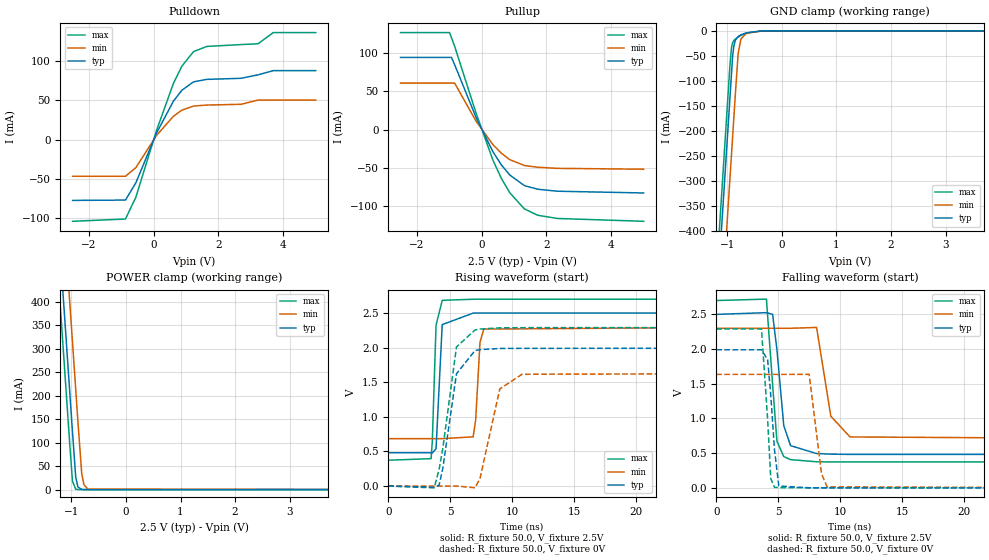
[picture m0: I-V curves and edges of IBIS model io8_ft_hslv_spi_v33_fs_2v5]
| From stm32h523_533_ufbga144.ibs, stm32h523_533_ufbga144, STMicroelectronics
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[Model]   io8_ft_hslv_spi_v33_fs_2v5
Model_type I/O
Polarity   Non-Inverting
Enable   Active-Low
| CAP_THRESHOLD on pad IOFT is "UDTCAPC" :
| Rising=20.0% of vddiom   Falling=80.0% of vddiom
| C_comp min and max val. don't necessarily correlate with the min and max pvt
| but are the smallest and greatest pad capacitance found.
| var   typ   min   max
C_comp   3.86841pF  3.83555pF  3.96274pF
|C_comp_pullup   2.45380pF  2.33565pF  2.34210pF
|C_comp_pulldown   1.41461pF  1.49990pF  1.62064pF
Vinl = 690.0mV
Vinh = 1.89V
Vmeas = 1.25V   | Reference voltage for timing measurements
Cref  = 50.0pF   | Timing specification test load capacitance value
Rref  = 100.0MOhm   | Timing specification test load resistance value
Vref  = 1.25V   | Timing specification test load voltage
[Model Spec]
| TIME_THRESHOLD on pin ZIV33M is "CMOS" :
| Rising=40.0% of vddiom   Falling=60.0% of vddiom
Vinl 978.80000mV 906.80000mV 1.05480V
Vinh 1.39920V 1.29220V 1.48720V
| variable   typ   min   max
[Temperature Range] 25.0 125.0 -40.0
| variable   typ   min   max
[Voltage Range] 2.5V 2.3V 2.7V
| variable   typ   min   max
[POWER Clamp Reference] 2.5V 2.3V 2.7V
| variable   typ   min   max
[GND Clamp Reference] 0V 0V 0V
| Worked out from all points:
|   slope of the pulldown table from 0 to 0.375 V, typ, clamps not added: 11.5 ohm
|   slope of the pullup table from 0 to 0.375 V, typ, clamps not added: 12.3 ohm
|   GND clamp passes 1 mA (typ) near -0.52 V on its own axis
|   POWER clamp passes 1 mA (typ) near -0.84 V on its own axis
|   rising waveform, R_fixture 50.0, V_fixture 2.5V: 20-80 % time 254ps typ, 282ps min, 245ps max; typ from 0.481 V to 2.5 V
|   falling waveform, R_fixture 50.0, V_fixture 2.5V: 20-80 % time 609ps typ, 780ps min, 487ps max; typ from 2.5 V to 0.481 V
|   rising waveform, R_fixture 50.0, V_fixture 0V: 20-80 % time 929ps typ, 1.15ns min, 979ps max; typ from 0 V to 1.99 V
|   falling waveform, R_fixture 50.0, V_fixture 0V: 20-80 % time 481ps typ, 588ps min, 376ps max; typ from 1.99 V to 0 V
[POWER Clamp]
-2.5V     2.708A     2.899A     2.597A
-1.23V    548.8mA    740.2mA    437.5mA
-1.16V    429.8mA    621.2mA    318.5mA
-1.12V    361.8mA    553.2mA    250.5mA
-1.03V    208.8mA    400.2mA    97.53mA
-980mV    123.8mA    315.2mA    17.95mA
-920mV    26.3mA     213.2mA    906uA
-880mV    5.543mA    145.2mA    123.7uA
-810mV    363.5uA    33.6mA     3.797uA
-770mV    76.62uA    10.47mA    518.8nA
-700mV    5.026uA    1.361mA    16.09nA
5V        0A         0A         0A
[GND Clamp]
-2.5V     -2.77A     -2.931A    -2.704A
-1.21V    -576.8mA   -738.1mA   -511.3mA
-950mV    -134.8mA   -296.1mA   -69.34mA
-920mV    -83.82mA   -245.1mA   -32.48mA
-900mV    -50.56mA   -211.1mA   -24.02mA
-880mV    -31.31mA   -177.1mA   -19.85mA
-850mV    -18.7mA    -126.1mA   -16.34mA
-800mV    -11.46mA   -46.18mA   -12.45mA
-750mV    -8.203mA   -16.63mA   -9.325mA
-650mV    -4.063mA   -4.987mA   -4.427mA
-360mV    -35.05uA   -165.1uA   -9.564uA
5V        7.96nA     1.282uA    294pA
| variable   typ   min   max
[Pullup Reference] 2.5V 2.3V 2.7V
| variable   typ   min   max
[Pulldown Reference] 0V 0V 0V
[Pullup]
-2.5V     94.45mA    60.85mA    126.9mA
-990mV    94.45mA    60.85mA    126.9mA
-930mV    94.45mA    60.85mA    120.4mA
-830mV    84.85mA    60.85mA    108.9mA
-170mV    16.04mA    11.14mA    21.66mA
350mV     -28.77mA   -19.46mA   -39.69mA
610mV     -45.89mA   -30.7mA    -63.55mA
870mV     -59.15mA   -39.06mA   -82.32mA
1.32V     -72.97mA   -46.73mA   -103.4mA
1.73V     -77.7mA    -49.01mA   -111.7mA
2.34V     -80.33mA   -50.46mA   -115.9mA
5V        -82.59mA   -51.55mA   -119.6mA
[Pulldown]
-2.5V     -77.63mA   -46.85mA   -104.3mA
-870mV    -77.24mA   -46.85mA   -101.4mA
-550mV    -55.3mA    -35.88mA   -73.72mA
90mV      8.401mA    5.299mA    11.79mA
610mV     49.03mA    29.76mA    71.69mA
870mV     62.92mA    37.48mA    93.62mA
1.23V     73.63mA    42.72mA    112.2mA
1.64V     76.78mA    44.01mA    118.8mA
2.7V      78.15mA    44.99mA    121.2mA
3.22V     82.58mA    50.35mA    122.2mA
3.69V     87.93mA    50.35mA    136.5mA
5V        87.93mA    50.35mA    136.5mA
[Ramp]
dV/dt_r 1.19372V/924.90149ps 981.18147mV/1.14692ns 1.37325V/977.3904ps
dV/dt_f 1.21165V/608.18888ps 969.26199mV/760.35677ps 1.39628V/486.33544ps
R_load = 50.0
| Removed startup time: 0s 0s 0s  .
| Removed end time: 33.75ns.
[Rising Waveform]
R_fixture   = 50.0
V_fixture   = 2.5V
V_fixture_min = 2.3V
V_fixture_max = 2.7V
0s        480.6mV    684.6mV    372.9mV
3.45ns    481mV      684.6mV    395.6mV
3.55ns    478mV      684.6mV    651.1mV
3.85ns    538.8mV    684.6mV    2.324V
4.35ns    2.332V     684.6mV    2.683V
6.85ns    2.498V     710.6mV    2.698V
7.05ns    2.499V     954.1mV    2.699V
7.4ns     2.499V     2.075V     2.699V
7.7ns     2.499V     2.267V     2.699V
33.75ns   2.5V       2.3V       2.7V
| Removed startup time: 0s 0s 0s  .
| Removed end time: 58.75ns.
[Falling Waveform]
R_fixture   = 50.0
V_fixture   = 2.5V
V_fixture_min = 2.3V
V_fixture_max = 2.7V
0s        2.5V       2.3V       2.7V
4.05ns    2.525V     2.3V       2.72V
4.55ns    2.501V     2.3V       1.486V
4.9ns     1.987V     2.3V       670.2mV
5.45ns    896.5mV    2.3V       450.3mV
6ns       608.3mV    2.3V       407mV
8.1ns     494.4mV    2.312V     375.9mV
9.25ns    485.8mV    1.033V     373.9mV
10.8ns    482.1mV    733.7mV    373.1mV
58.75ns   480.6mV    684.6mV    372.9mV
| Removed startup time: 0s 0s 0s  .
| Removed end time: 58.7ns.
[Rising Waveform]
R_fixture   = 50.0
V_fixture   = 0V
V_fixture_min = 0V
V_fixture_max = 0V
0s        184.3nV    425.6nV    144.4nV
3.7ns     -17.77mV   -118.8nV   -26.28mV
4.1ns     13.84mV    -230.2nV   241.7mV
4.4ns     259.3mV    -229.3nV   549mV
5.5ns     1.622V     -2.504uV   2.009V
7ns       1.958V     -24.91mV   2.255V
7.4ns     1.97V      110.4mV    2.268V
9ns       1.987V     1.403V     2.285V
10.8ns    1.989V     1.615V     2.288V
58.7ns    1.99V      1.635V     2.289V
| Removed startup time: 0s 0s 0s  .
| Removed end time: 33.7ns.
[Falling Waveform]
R_fixture   = 50.0
V_fixture   = 0V
V_fixture_min = 0V
V_fixture_max = 0V
0s        1.99V      1.635V     2.289V
3.65ns    1.99V      1.635V     2.291V
4.15ns    1.845V     1.635V     978.7mV
4.4ns     1.332V     1.635V     132.5mV
4.7ns     552.4mV    1.635V     7.328mV
5.05ns    26.41mV    1.635V     3.603mV
7.5ns     999.1uV    1.636V     594.7uV
8.5ns     511.2uV    202.5mV    284.8uV
8.95ns    384uV      14.72mV    207.7uV
33.7ns    197.6nV    2.782uV    38.82nV
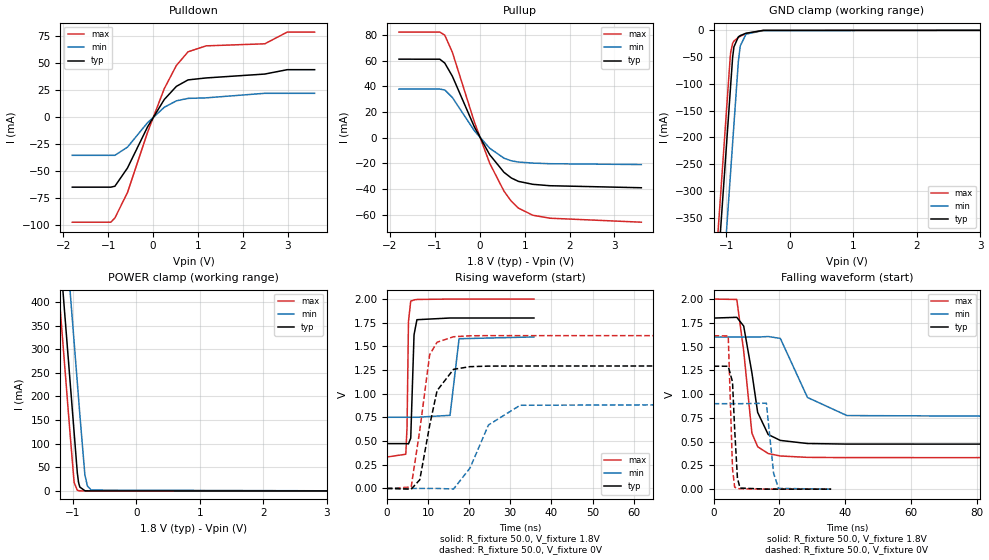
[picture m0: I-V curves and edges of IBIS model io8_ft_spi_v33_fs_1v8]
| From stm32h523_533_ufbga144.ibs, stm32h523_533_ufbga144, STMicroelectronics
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[Model]   io8_ft_spi_v33_fs_1v8
Model_type I/O
Polarity   Non-Inverting
Enable   Active-Low
| CAP_THRESHOLD on pad IOFT is "UDTCAPC" :
| Rising=20.0% of vddiom   Falling=80.0% of vddiom
| C_comp min and max val. don't necessarily correlate with the min and max pvt
| but are the smallest and greatest pad capacitance found.
| var   typ   min   max
C_comp   3.69208pF  3.66955pF  3.86721pF
|C_comp_pullup   2.28970pF  2.21730pF  2.21540pF
|C_comp_pulldown   1.40238pF  1.45225pF  1.65181pF
Vinl = 480.0mV
Vinh = 1.4V
Vmeas = 900.0mV   | Reference voltage for timing measurements
Cref  = 50.0pF   | Timing specification test load capacitance value
Rref  = 100.0MOhm   | Timing specification test load resistance value
Vref  = 900.0mV   | Timing specification test load voltage
[Model Spec]
| TIME_THRESHOLD on pin ZIV33M is "CMOS" :
| Rising=40.0% of vddiom   Falling=60.0% of vddiom
Vinl 693.80000mV 621.80000mV 774.80000mV
Vinh 1.05820V 933.20000mV 1.16320V
| variable   typ   min   max
[Temperature Range] 25.0 125.0 -40.0
| variable   typ   min   max
[Voltage Range] 1.8V 1.6V 2.0V
| variable   typ   min   max
[POWER Clamp Reference] 1.8V 1.6V 2.0V
| variable   typ   min   max
[GND Clamp Reference] 0V 0V 0V
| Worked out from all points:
|   slope of the pulldown table from 0 to 0.27 V, typ, clamps not added: 15.8 ohm
|   slope of the pullup table from 0 to 0.27 V, typ, clamps not added: 17.1 ohm
|   GND clamp passes 1 mA (typ) near -0.52 V on its own axis
|   POWER clamp passes 1 mA (typ) near -0.84 V on its own axis
|   rising waveform, R_fixture 50.0, V_fixture 1.8V: 20-80 % time 418ps typ, 862ps min, 292ps max; typ from 0.474 V to 1.8 V
|   falling waveform, R_fixture 50.0, V_fixture 1.8V: 20-80 % time 4.01ns typ, 7.25ns min, 2.73ns max; typ from 1.8 V to 0.474 V
|   rising waveform, R_fixture 50.0, V_fixture 0V: 20-80 % time 3.42ns typ, 6.19ns min, 2.57ns max; typ from 0 V to 1.29 V
|   falling waveform, R_fixture 50.0, V_fixture 0V: 20-80 % time 1.1ns typ, 1.58ns min, 754ps max; typ from 1.29 V to 0 V
[POWER Clamp]
-1.8V     1.518A     1.709A     1.407A
-1.23V    548.8mA    740.2mA    437.5mA
-1.16V    429.8mA    621.2mA    318.5mA
-1.05V    242.8mA    434.2mA    131.5mA
-980mV    123.8mA    315.2mA    17.95mA
-930mV    38.81mA    230.2mA    1.49mA
-910mV    17.82mA    196.2mA    550.8uA
-890mV    8.18mA     162.2mA    203.5uA
-810mV    363.5uA    33.6mA     3.797uA
-770mV    76.62uA    10.47mA    518.8nA
-710mV    7.416uA    1.822mA    26.34nA
3.6V      0A         0A         0A
[GND Clamp]
-1.8V     -1.579A    -1.74A     -1.515A
-1.24V    -627.3mA   -788.3mA   -562.7mA
-1.05V    -304.3mA   -465.3mA   -239.7mA
-940mV    -117.3mA   -278.3mA   -52.69mA
-930mV    -100.3mA   -261.3mA   -40.52mA
-900mV    -50.11mA   -210.3mA   -24.23mA
-880mV    -30.95mA   -176.3mA   -20.02mA
-810mV    -12.18mA   -57.97mA   -13.23mA
-780mV    -9.807mA   -29.1mA    -11.19mA
-690mV    -5.41mA    -7.142mA   -6.184mA
-420mV    -170.4uA   -446.1uA   -81.94uA
3.6V      5.755nA    953.4nA    228.2pA
| variable   typ   min   max
[Pullup Reference] 1.8V 1.6V 2.0V
| variable   typ   min   max
[Pulldown Reference] 0V 0V 0V
[Pullup]
-1.8V     61.29mA    37.94mA    82.42mA
-890mV    61.26mA    37.94mA    82.42mA
-780mV    58.24mA    37.25mA    79.99mA
-610mV    47.92mA    31.37mA    66.59mA
-120mV    8.372mA    5.391mA    12.2mA
220mV     -13.2mA    -8.17mA    -19.85mA
540mV     -27mA      -15.96mA   -41.75mA
700mV     -31.35mA   -17.98mA   -49.41mA
860mV     -34.04mA   -18.97mA   -54.88mA
1.18V     -36.34mA   -19.79mA   -60.45mA
1.56V     -37.44mA   -20.28mA   -62.79mA
3.6V      -39.03mA   -20.93mA   -65.9mA
[Pulldown]
-1.8V     -65.02mA   -35.56mA   -97.42mA
-940mV    -65.02mA   -35.56mA   -97.42mA
-850mV    -64.17mA   -35.56mA   -93.49mA
-570mV    -47.32mA   -28.01mA   -70.04mA
-120mV    -9.088mA   -5.279mA   -14.07mA
250mV     16.04mA    8.832mA    26.05mA
520mV     28.19mA    14.82mA    47.53mA
780mV     34.17mA    17.07mA    60.14mA
1.18V     35.97mA    17.56mA    65.65mA
2.49V     39.57mA    21.77mA    67.55mA
2.99V     43.62mA    21.77mA    78.38mA
3.6V      43.62mA    21.77mA    78.38mA
[Ramp]
dV/dt_r 776.15867mV/3.3837ns 539.54929mV/5.61536ns 968.54376mV/2.56836ns
dV/dt_f 795.78723mV/3.56197ns 508.98074mV/6.71108ns 1.00099V/2.72983ns
R_load = 50.0
| Removed startup time: 0s 0s 0s  .
| Removed end time: 35.75ns.
[Rising Waveform]
R_fixture   = 50.0
V_fixture   = 1.8V
V_fixture_min = 1.6V
V_fixture_max = 2.0V
0s        473.7mV    751.7mV    331.7mV
4.6ns     473.7mV    751.7mV    361.4mV
4.9ns     472.6mV    751.7mV    647.1mV
5.25ns    470.6mV    751.7mV    1.764V
5.8ns     531.7mV    751.7mV    1.978V
6.6ns     1.622V     751.7mV    1.991V
7.3ns     1.782V     751.7mV    1.996V
15.35ns   1.8V       772.1mV    2V
17.55ns   1.8V       1.581V     2V
35.75ns   1.8V       1.6V       2V
| Removed startup time: 0s 0s 0s  .
| Removed end time: 198.75ns.
[Falling Waveform]
R_fixture   = 50.0
V_fixture   = 1.8V
V_fixture_min = 1.6V
V_fixture_max = 2.0V
0s        1.8V       1.6V       2V
7.05ns    1.808V     1.6V       1.996V
9.15ns    1.716V     1.6V       1.454V
11.65ns   1.224V     1.6V       590.2mV
13.4ns    808.1mV    1.6V       446.6mV
16.6ns    575mV      1.606V     375mV
20.3ns    512.9mV    1.586V     349.1mV
28.55ns   480.3mV    964.9mV    334.6mV
40.55ns   474.3mV    774.4mV    332mV
198.8ns   473.7mV    751.7mV    331.7mV
| Removed startup time: 0s 0s 0s  .
| Removed end time: 198.6ns.
[Rising Waveform]
R_fixture   = 50.0
V_fixture   = 0V
V_fixture_min = 0V
V_fixture_max = 0V
0s        178.3nV    440.4nV    128.8nV
5.9ns     -7.616mV   447nV      14.22mV
8ns       91.75mV    454.7nV    614.4mV
10.4ns    666.3mV    477.6nV    1.413V
12.2ns    1.033V     694.6nV    1.544V
16.2ns    1.258V     -6.322mV   1.602V
20.2ns    1.286V     215.2mV    1.612V
24.7ns    1.292V     670.6mV    1.614V
32.4ns    1.293V     878.5mV    1.614V
198.6ns   1.294V     899.2mV    1.614V
| Removed startup time: 0s 0s 0s  .
| Removed end time: 35.75ns.
[Falling Waveform]
R_fixture   = 50.0
V_fixture   = 0V
V_fixture_min = 0V
V_fixture_max = 0V
0s        1.294V     899.3mV    1.614V
4.45ns    1.293V     899.3mV    1.612V
5.75ns    1.128V     899.3mV    216.6mV
6.4ns     633.5mV    899.3mV    21.75mV
7.25ns    114mV      899.3mV    6.306mV
8.05ns    11.9mV     899.3mV    4.344mV
16.05ns   443.9uV    904.4mV    280.7uV
18.25ns   280.8uV    168mV      182.2uV
19.75ns   205.9uV    8.122mV    135uV
35.75ns   7.312uV    292.6uV    5.237uV
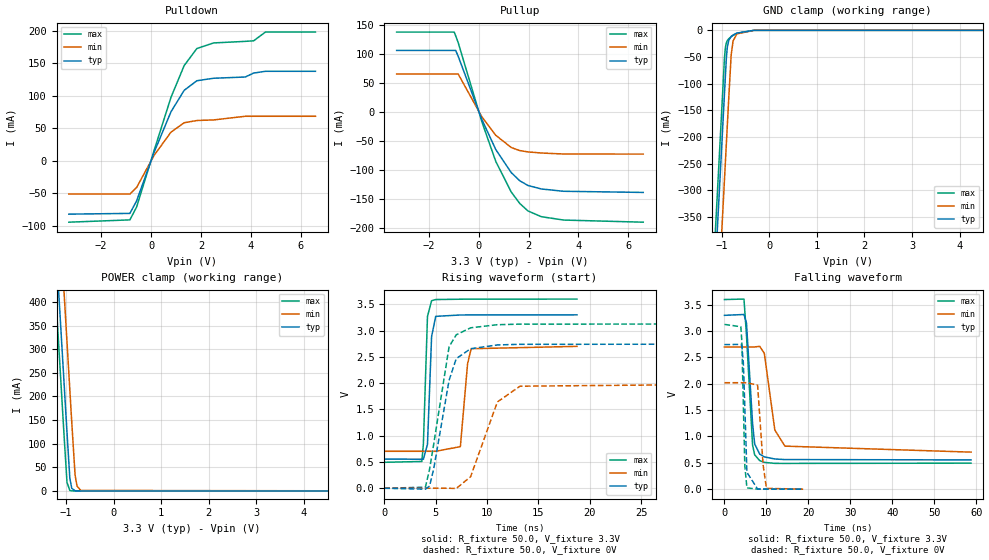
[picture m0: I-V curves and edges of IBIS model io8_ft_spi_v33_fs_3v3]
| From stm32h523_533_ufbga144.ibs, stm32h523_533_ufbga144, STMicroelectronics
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[Model]   io8_ft_spi_v33_fs_3v3
Model_type I/O
Polarity   Non-Inverting
Enable   Active-Low
| CAP_THRESHOLD on pad IOFT is "UDTCAPC" :
| Rising=20.0% of vddiom   Falling=80.0% of vddiom
| C_comp min and max val. don't necessarily correlate with the min and max pvt
| but are the smallest and greatest pad capacitance found.
| var   typ   min   max
C_comp   3.95302pF  3.95030pF  4.00762pF
|C_comp_pullup   2.45780pF  2.54045pF  2.38960pF
|C_comp_pulldown   1.49522pF  1.40985pF  1.61802pF
Vinl = 810.0mV
Vinh = 2.52V
Vmeas = 1.65V   | Reference voltage for timing measurements
Cref  = 50.0pF   | Timing specification test load capacitance value
Rref  = 100.0MOhm   | Timing specification test load resistance value
Vref  = 1.65V   | Timing specification test load voltage
[Model Spec]
| TIME_THRESHOLD on pin ZIV33M is "CMOS" :
| Rising=40.0% of vddiom   Falling=60.0% of vddiom
Vinl 1.28680V 1.06380V 1.39380V
Vinh 1.76920V 1.48820V 1.89120V
| variable   typ   min   max
[Temperature Range] 25.0 125.0 -40.0
| variable   typ   min   max
[Voltage Range] 3.3V 2.7V 3.6V
| variable   typ   min   max
[POWER Clamp Reference] 3.3V 2.7V 3.6V
| variable   typ   min   max
[GND Clamp Reference] 0V 0V 0V
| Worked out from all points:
|   slope of the pulldown table from 0 to 0.495 V, typ, clamps not added: 10 ohm
|   slope of the pullup table from 0 to 0.495 V, typ, clamps not added: 10 ohm
|   GND clamp passes 1 mA (typ) near -0.52 V on its own axis
|   POWER clamp passes 1 mA (typ) near -0.84 V on its own axis
|   rising waveform, R_fixture 50.0, V_fixture 3.3V: 20-80 % time 294ps typ, 397ps min, 270ps max; typ from 0.556 V to 3.3 V
|   falling waveform, R_fixture 50.0, V_fixture 3.3V: 20-80 % time 1.26ns typ, 2.11ns min, 1.22ns max; typ from 3.3 V to 0.556 V
|   rising waveform, R_fixture 50.0, V_fixture 0V: 20-80 % time 1.48ns typ, 2.2ns min, 1.44ns max; typ from 0 V to 2.74 V
|   falling waveform, R_fixture 50.0, V_fixture 0V: 20-80 % time 629ps typ, 936ps min, 522ps max; typ from 2.74 V to 0 V
[POWER Clamp]
-3.3V     4.068A     4.259A     3.957A
-1.25V    582.8mA    774.2mA    471.5mA
-1.21V    514.8mA    706.2mA    403.5mA
-1.13V    378.8mA    570.2mA    267.5mA
-1.04V    225.8mA    417.2mA    114.5mA
-980mV    123.8mA    315.2mA    17.95mA
-920mV    26.3mA     213.2mA    906uA
-880mV    5.543mA    145.2mA    123.7uA
-810mV    363.5uA    33.6mA     3.798uA
-770mV    76.62uA    10.47mA    519.4nA
-690mV    3.409uA    1.017mA    10.47nA
6.6V      0A         0A         0A
[GND Clamp]
-3.3V     -4.13A     -4.291A    -4.063A
-1.25V    -644.7mA   -806.4mA   -578.1mA
-940mV    -117.7mA   -279.4mA   -51.06mA
-920mV    -83.75mA   -245.4mA   -31.43mA
-900mV    -50.5mA    -211.4mA   -23.14mA
-880mV    -31.27mA   -177.4mA   -19.1mA
-850mV    -18.68mA   -126.4mA   -15.73mA
-800mV    -11.46mA   -46.4mA    -12.03mA
-760mV    -8.752mA   -20.02mA   -9.606mA
-680mV    -5.122mA   -6.673mA   -5.579mA
-320mV    -10.25uA   -73.91uA   -1.981uA
6.6V      10.49nA    1.843uA    393.6pA
| variable   typ   min   max
[Pullup Reference] 3.3V 2.7V 3.6V
| variable   typ   min   max
[Pulldown Reference] 0V 0V 0V
[Pullup]
-3.3V     106.4mA    65.64mA    138.2mA
-990mV    106.4mA    65.64mA    138.2mA
-930mV    106.4mA    65.64mA    131.8mA
-830mV    96.37mA    65.64mA    120mA
120mV     -12.97mA   -8.371mA   -17mA
680mV     -65.16mA   -40.47mA   -85.72mA
1.3V      -105mA     -61.6mA    -138.6mA
1.64V     -119mA     -66.82mA   -158.3mA
1.97V     -127.3mA   -69.18mA   -171.3mA
2.51V     -133.3mA   -71.08mA   -181.3mA
3.4V      -137.3mA   -72.8mA    -187.1mA
6.6V      -139.3mA   -72.98mA   -190.8mA
[Pulldown]
-3.3V     -82.42mA   -51.49mA   -94.82mA
-850mV    -81.27mA   -51.49mA   -91.26mA
-580mV    -62.01mA   -41.36mA   -71.41mA
120mV     12.61mA    7.999mA    15.37mA
800mV     75.3mA     43.94mA    97.52mA
1.33V     108.3mA    58.37mA    146.5mA
1.84V     123.1mA    61.83mA    172.7mA
2.51V     126.9mA    62.7mA     181.3mA
3.78V     128.8mA    68.32mA    183.7mA
4.12V     134.9mA    68.32mA    184.6mA
4.59V     137.6mA    68.32mA    198mA
6.6V      137.6mA    68.32mA    198mA
[Ramp]
dV/dt_r 1.64651V/1.4746ns 1.21266V/2.19474ns 1.87653V/1.43773ns
dV/dt_f 1.64666V/1.26129ns 1.19801V/2.06017ns 1.86387V/1.21073ns
R_load = 50.0
| Removed startup time: 0s 0s 0s  .
| Removed end time: 18.75ns.
[Rising Waveform]
R_fixture   = 50.0
V_fixture   = 3.3V
V_fixture_min = 2.7V
V_fixture_max = 3.6V
0s        555.6mV    703.3mV    493.6mV
3.65ns    551.9mV    703.3mV    509.8mV
3.8ns     551.3mV    703.3mV    835.2mV
4.2ns     835.8mV    703.3mV    3.27V
4.6ns     2.886V     703.3mV    3.568V
5ns       3.271V     703.3mV    3.591V
7.4ns     3.297V     791.9mV    3.597V
8.1ns     3.298V     2.366V     3.598V
8.45ns    3.298V     2.655V     3.598V
18.75ns   3.3V       2.7V       3.6V
| Removed startup time: 0s 0s 0s  .
| Removed end time: 58.75ns.
[Falling Waveform]
R_fixture   = 50.0
V_fixture   = 3.3V
V_fixture_min = 2.7V
V_fixture_max = 3.6V
0s        3.3V       2.7V       3.6V
4.65ns    3.316V     2.7V       3.609V
5.25ns    3.152V     2.7V       2.919V
6.7ns     1.245V     2.7V       836.6mV
7.2ns     858.7mV    2.7V       651.2mV
8.4ns     665.5mV    2.712V     541.8mV
9.5ns     613.3mV    2.579V     509.2mV
12ns      572.8mV    1.122V     489.6mV
14.4ns    562.1mV    817.3mV    489mV
58.75ns   555.6mV    703.3mV    493.6mV
| Removed startup time: 0s 0s 0s  .
| Removed end time: 58.7ns.
[Rising Waveform]
R_fixture   = 50.0
V_fixture   = 0V
V_fixture_min = 0V
V_fixture_max = 0V
0s        227.9nV    417nV      212.4nV
4ns       -17.4mV    439.2nV    20.33mV
4.4ns     40.77mV    433.7nV    360.3mV
4.8ns     362.5mV    651.6nV    832.1mV
6.3ns     2.053V     170.2uV    2.692V
7ns       2.467V     -5.36mV    2.92V
8.4ns     2.655V     221.2mV    3.053V
11ns      2.727V     1.642V     3.112V
13.2ns    2.739V     1.942V     3.123V
58.7ns    2.744V     2.021V     3.128V
| Removed startup time: 0s 0s 0s  .
| Removed end time: 18.75ns.
[Falling Waveform]
R_fixture   = 50.0
V_fixture   = 0V
V_fixture_min = 0V
V_fixture_max = 0V
0s        2.744V     2.021V     3.128V
3.9ns     2.749V     2.021V     3.084V
4.15ns    2.722V     2.021V     2.798V
4.5ns     2.398V     2.021V     1.61V
4.85ns    1.572V     2.021V     449mV
5.35ns    320.1mV    2.021V     24.18mV
7.9ns     1.864mV    1.974V     1.37mV
9.2ns     1.207mV    467.3mV    946.7uV
10ns      964.9uV    15.86mV    779.1uV
18.75ns   66.51uV    470.5uV    78.64uV
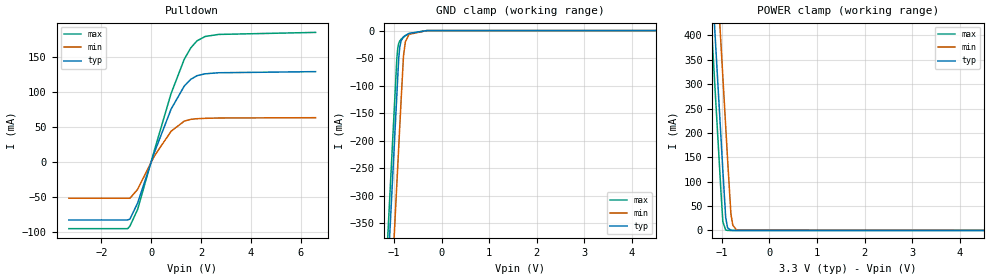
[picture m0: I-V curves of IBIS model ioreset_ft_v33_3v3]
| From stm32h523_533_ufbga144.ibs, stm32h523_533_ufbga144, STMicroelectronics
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[Model]   ioreset_ft_v33_3v3
Model_type I/O_open_drain
Polarity   Inverting
Enable   Active-Low
| CAP_THRESHOLD on pad IOFT is "UDTCAPC" :
| Rising=20.0% of vddiom   Falling=80.0% of vddiom
| C_comp min and max val. don't necessarily correlate with the min and max pvt
| but are the smallest and greatest pad capacitance found.
| var   typ   min   max
C_comp   3.41800pF  3.38985pF  3.43615pF
|C_comp_pulldown   3.41800pF  3.38985pF  3.43615pF
Vinl = 1.35V
Vinh = 1.8V
Vmeas = 1.65V   | Reference voltage for timing measurements
Cref  = 50.0pF   | Timing specification test load capacitance value
Rref  = 1.0MOhm   | Timing specification test load resistance value
Vref  = 1.815V   | Timing specification test load voltage
[Model Spec]
| TIME_THRESHOLD on pin ZIV33M is "CMOS" :
| Rising=40.0% of vddiom   Falling=60.0% of vddiom
Vinl 1.28980V 1.06780V 1.39680V
Vinh 1.76120V 1.48020V 1.88320V
| variable   typ   min   max
[Temperature Range] 25.0 125.0 -40.0
| variable   typ   min   max
[Voltage Range] 3.3V 2.7V 3.6V
| variable   typ   min   max
[POWER Clamp Reference] 3.3V 2.7V 3.6V
| variable   typ   min   max
[GND Clamp Reference] 0V 0V 0V
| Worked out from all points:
|   slope of the pulldown table from 0 to 0.495 V, typ, clamps not added: 10 ohm
|   GND clamp passes 1 mA (typ) near -0.52 V on its own axis
|   POWER clamp passes 1 mA (typ) near -0.84 V on its own axis
[POWER Clamp]
-3.3V     4.068A     4.259A     3.957A
-1.25V    582.8mA    774.2mA    471.5mA
-1.19V    480.8mA    672.2mA    369.5mA
-1.13V    378.8mA    570.2mA    267.5mA
-1.02V    191.8mA    383.2mA    80.53mA
-980mV    123.8mA    315.2mA    17.95mA
-920mV    26.3mA     213.2mA    906uA
-880mV    5.543mA    145.2mA    123.7uA
-810mV    363.5uA    33.6mA     3.797uA
-770mV    76.62uA    10.47mA    518.7nA
-690mV    3.405uA    1.017mA    9.758nA
6.6V      0A         0A         0A
[GND Clamp]
-3.3V     -4.13A     -4.291A    -4.063A
-1.25V    -644.7mA   -806.4mA   -578.1mA
-940mV    -117.7mA   -279.4mA   -51.06mA
-920mV    -83.75mA   -245.4mA   -31.43mA
-900mV    -50.5mA    -211.4mA   -23.13mA
-880mV    -31.27mA   -177.4mA   -19.09mA
-850mV    -18.67mA   -126.4mA   -15.72mA
-800mV    -11.45mA   -46.39mA   -12.02mA
-760mV    -8.748mA   -20.02mA   -9.597mA
-680mV    -5.116mA   -6.67mA    -5.572mA
-310mV    -7.215uA   -58.57uA   -1.252uA
6.6V      518.6pA    70.15nA    177.4pA
| variable   typ   min   max
[Pullup Reference] 3.3V 2.7V 3.6V
| variable   typ   min   max
[Pulldown Reference] 0V 0V 0V
[Pulldown]
-3.3V     -82.42mA   -51.49mA   -94.82mA
-940mV    -82.42mA   -51.49mA   -94.82mA
-850mV    -81.27mA   -51.49mA   -91.27mA
-540mV    -58.27mA   -38.85mA   -67.33mA
120mV     12.61mA    7.999mA    15.37mA
800mV     75.3mA     43.94mA    97.52mA
1.33V     108.3mA    58.37mA    146.5mA
1.59V     117.9mA    60.9mA     162.6mA
1.84V     123.1mA    61.83mA    172.7mA
2.17V     125.8mA    62.37mA    179mA
2.7V      127.3mA    62.83mA    181.9mA
6.6V      128.9mA    63.27mA    184.8mA
[Ramp]
dV/dt_r 1.6582V/292.66916ps 1.1915V/431.75324ps 1.87336V/258.22006ps
dV/dt_f 1.64668V/6.81288ns 1.19801V/14.85647ns 1.86387V/4.47675ns
R_load = 50.0
| Removed startup time: 0s 0s 0s  .
| Removed end time: 99.99us.
|[End]
